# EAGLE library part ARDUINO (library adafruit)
Arduino Diecimila/Duemilanove Make a shield with ease, this package has all the named pins as well as the two mounting drill holes and an outline of the USB and DC power connector. The outline is on the DIMENSION layer, so if your board house uses it they will cut the outline to match. http://www.ladyada.net/library/pcb/eaglelibrary.html

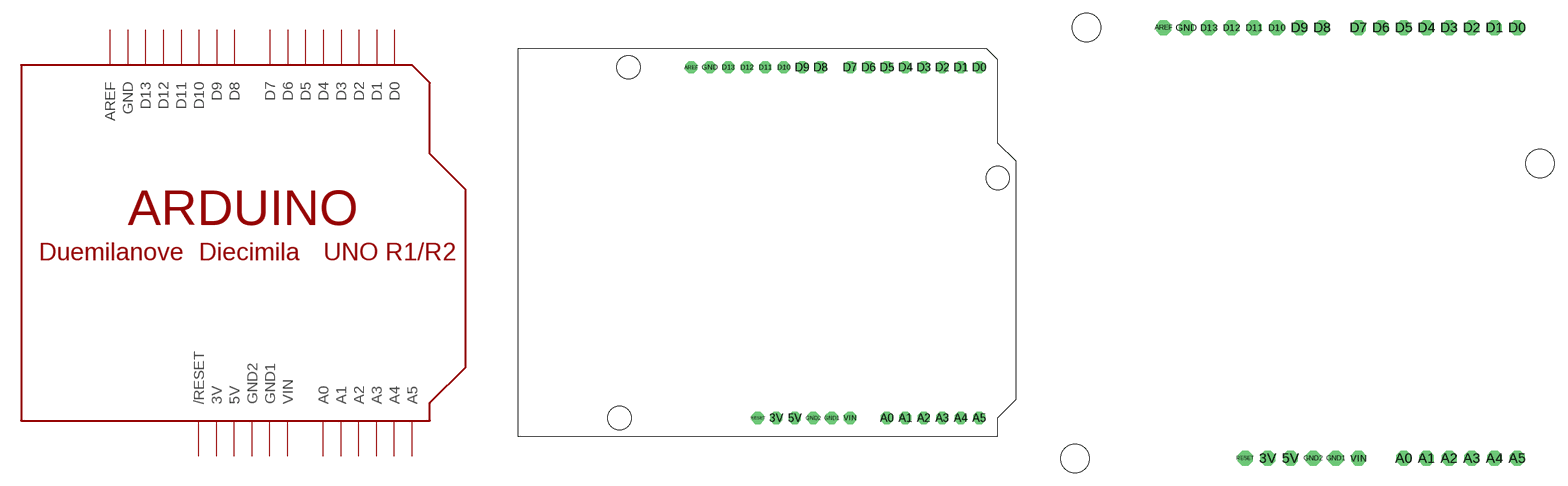
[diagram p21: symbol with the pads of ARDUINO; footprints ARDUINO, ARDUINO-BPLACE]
Designator prefix -

## ARDUINOUNO  [ARDUINO]
3V  3V  pwr
5V  5V  pwr
A0  A0
A1  A1
A2  A2
A3  A3
A4  A4
A5  A5
AREF  AREF
D0  D0
D1  D1
D2  D2
D3  D3
D4  D4
D5  D5
D6  D6
D7  D7
D8  D8
D9  D9
D10  D10
D11  D11
D12  D12
D13  D13
GND  GND  pwr
GND1  GND1  pwr
GND2  GND2  pwr
RESET  /RESET
VIN  VIN  pwr

## ARDUINO-BPLACE  [ARDUINO-BPLACE]
Pads as for ARDUINO

## ARDUINO-NOHOLE  [ARDUINO-NOHOLE]
Pads as for ARDUINO

## ARDUINO-NODIM  [ARDUINO-NODIM]
Pads as for ARDUINO

## Footprint ARDUINO (pad centres in mm)
Arduino Uno Make a shield with ease, this package has all the named pins as well as the two mounting drill holes and an outline of the USB and DC power connector. The outline is on the DIMENSION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
drill 1 pad 1.676 octagon: 3V 35.56,2.54; 5V 38.1,2.54; A0 50.8,2.54; A1 53.34,2.54; A2 55.88,2.54; A3 58.42,2.54; A4 60.96,2.54; A5 63.5,2.54; AREF 23.876,50.8; D0 63.5,50.8; D1 60.96,50.8; D2 58.42,50.8; D3 55.88,50.8; D4 53.34,50.8; D5 50.8,50.8; D6 48.26,50.8; D7 45.72,50.8; D8 41.656,50.8; D9 39.116,50.8; D10 36.576,50.8; D11 34.036,50.8; D12 31.496,50.8; D13 28.956,50.8; GND 26.416,50.8; GND1 43.18,2.54; GND2 40.64,2.54; RESET 33.02,2.54; VIN 45.72,2.54
hole 3.2 at 15.24,50.8
hole 3.2 at 66.04,35.56
hole 3.2 at 13.97,2.54

## Footprint ARDUINO-BPLACE (pad centres in mm)
drill 1 pad 1.676 octagon: 3V 35.56,2.54; 5V 38.1,2.54; A0 50.8,2.54; A1 53.34,2.54; A2 55.88,2.54; A3 58.42,2.54; A4 60.96,2.54; A5 63.5,2.54; AREF 23.876,50.8; D0 63.5,50.8; D1 60.96,50.8; D2 58.42,50.8; D3 55.88,50.8; D4 53.34,50.8; D5 50.8,50.8; D6 48.26,50.8; D7 45.72,50.8; D8 41.656,50.8; D9 39.116,50.8; D10 36.576,50.8; D11 34.036,50.8; D12 31.496,50.8; D13 28.956,50.8; GND 26.416,50.8; GND1 43.18,2.54; GND2 40.64,2.54; RESET 33.02,2.54; VIN 45.72,2.54
hole 3.2 at 15.24,50.8
hole 3.2 at 66.04,35.56
hole 3.2 at 13.97,2.54

## Footprint ARDUINO-NOHOLE (pad centres in mm)
drill 1 pad 1.676 octagon: 3V 35.56,2.54; 5V 38.1,2.54; A0 50.8,2.54; A1 53.34,2.54; A2 55.88,2.54; A3 58.42,2.54; A4 60.96,2.54; A5 63.5,2.54; AREF 23.876,50.8; D0 63.5,50.8; D1 60.96,50.8; D2 58.42,50.8; D3 55.88,50.8; D4 53.34,50.8; D5 50.8,50.8; D6 48.26,50.8; D7 45.72,50.8; D8 41.656,50.8; D9 39.116,50.8; D10 36.576,50.8; D11 34.036,50.8; D12 31.496,50.8; D13 28.956,50.8; GND 26.416,50.8; GND1 43.18,2.54; GND2 40.64,2.54; RESET 33.02,2.54; VIN 45.72,2.54

## Footprint ARDUINO-NODIM (pad centres in mm)
drill 1 pad 1.676 octagon: 3V 35.56,2.54; 5V 38.1,2.54; A0 50.8,2.54; A1 53.34,2.54; A2 55.88,2.54; A3 58.42,2.54; A4 60.96,2.54; A5 63.5,2.54; AREF 23.876,50.8; D0 63.5,50.8; D1 60.96,50.8; D2 58.42,50.8; D3 55.88,50.8; D4 53.34,50.8; D5 50.8,50.8; D6 48.26,50.8; D7 45.72,50.8; D8 41.656,50.8; D9 39.116,50.8; D10 36.576,50.8; D11 34.036,50.8; D12 31.496,50.8; D13 28.956,50.8; GND 26.416,50.8; GND1 43.18,2.54; GND2 40.64,2.54; RESET 33.02,2.54; VIN 45.72,2.54
hole 3.2 at 15.24,50.8
hole 3.2 at 66.04,35.56
hole 3.2 at 13.97,2.54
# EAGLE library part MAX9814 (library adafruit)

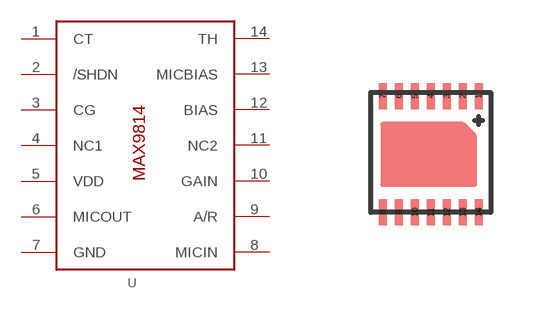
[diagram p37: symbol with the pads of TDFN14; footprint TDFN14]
Designator prefix -

## MAX9814TDFN  [TDFN14]
1  CT
2  /SHDN
3  CG
4  NC1  nc
5  VDD
6  MICOUT
7  GND
8  MICIN
9  A/R
10  GAIN
11  NC2  nc
12  BIAS
13  MICBIAS
14  TH

## Footprint TDFN14 (pad centres in mm)
smd 0.2 x 0.64: 1 1.2,1.4; 2 0.8,1.4; 3 0.4,1.4; 4 0,1.4; 5 -0.4,1.4; 6 -0.8,1.4; 7 -1.2,1.4; 8 -1.2,-1.5; 9 -0.8,-1.5; 10 -0.4,-1.5; 11 0,-1.5; 12 0.4,-1.5; 13 0.8,-1.5; 14 1.2,-1.5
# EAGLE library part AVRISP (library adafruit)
AVR ISP HEADER Standard 6 pin header for AVR programming

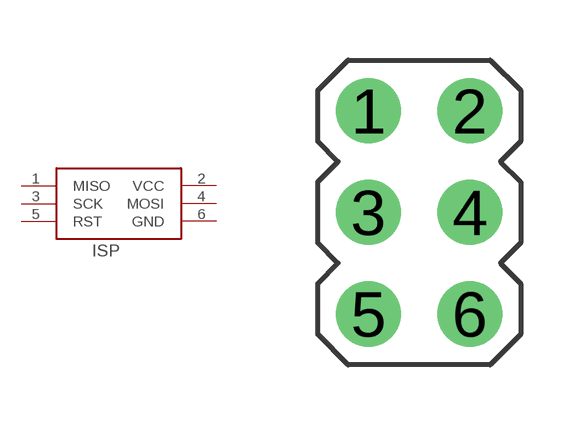
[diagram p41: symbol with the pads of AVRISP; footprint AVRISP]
Designator prefix ISP

## AVRISP-6  [AVRISP]
1  MISO  in
2  VCC  pwr
3  SCK  out
4  MOSI  out
5  RST  out
6  GND  pwr

## Footprint AVRISP (pad centres in mm)
drill 0.9 pad 1.626 round: 1 -1.27,2.54; 2 1.27,2.54; 3 -1.27,0; 4 1.27,0; 5 -1.27,-2.54; 6 1.27,-2.54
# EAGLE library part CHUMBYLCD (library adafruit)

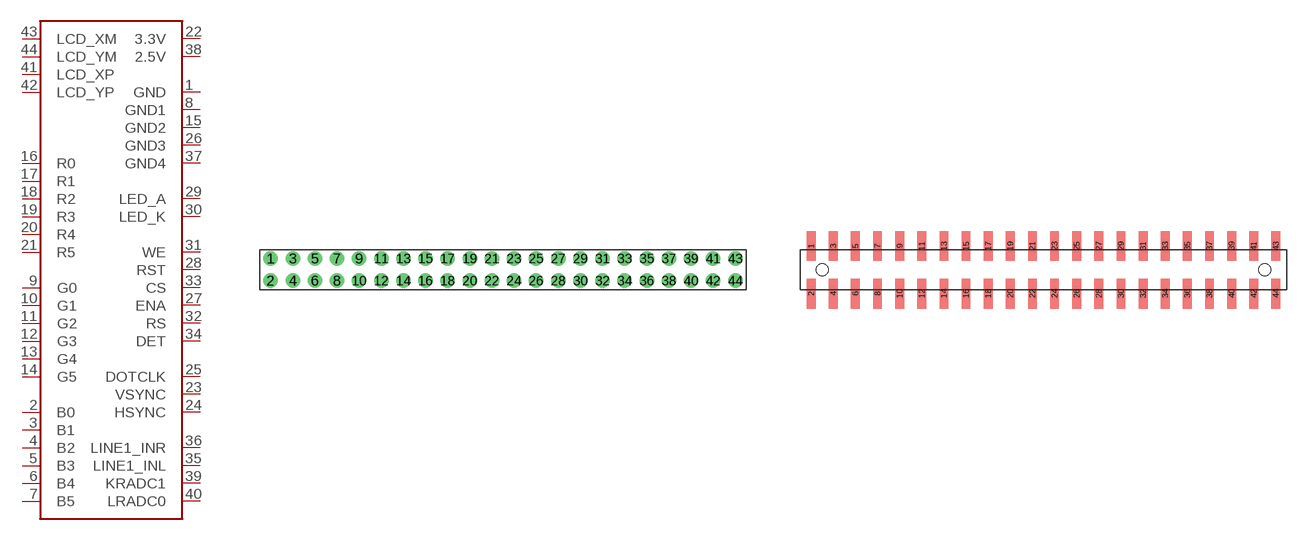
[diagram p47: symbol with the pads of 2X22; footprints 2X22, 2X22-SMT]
Designator prefix -

## CHUMBYLCD-THM  [2X22]
1  GND
2  B0
3  B1
4  B2
5  B3
6  B4
7  B5
8  GND1
9  G0
10  G1
11  G2
12  G3
13  G4
14  G5
15  GND2
16  R0
17  R1
18  R2
19  R3
20  R4
21  R5
22  3.3V
23  VSYNC
24  HSYNC
25  DOTCLK
26  GND3
27  ENA
28  RST
29  LED_A
30  LED_K
31  WE
32  RS
33  CS
34  DET
35  LINE1_INL
36  LINE1_INR
37  GND4
38  2.5V
39  KRADC1
40  LRADC0
41  LCD_XP
42  LCD_YP
43  LCD_XM
44  LCD_YM

## CHUMBYLCD-SMT  [2X22-SMT]
Pads as for 2X22

## Footprint 2X22 (pad centres in mm)
drill 0.8 round: 1 -21,1; 2 -21,-1; 3 -19,1; 4 -19,-1; 5 -17,1; 6 -17,-1; 7 -15,1; 8 -15,-1; 9 -13,1; 10 -13,-1; 11 -11,1; 12 -11,-1; 13 -9,1; 14 -9,-1; 15 -7,1; 16 -7,-1; 17 -5,1; 18 -5,-1; 19 -3,1; 20 -3,-1; 21 -1,1; 22 -1,-1; 23 1,1; 24 1,-1; 25 3,1; 26 3,-1; 27 5,1; 28 5,-1; 29 7,1; 30 7,-1; 31 9,1; 32 9,-1; 33 11,1; 34 11,-1; 35 13,1; 36 13,-1; 37 15,1; 38 15,-1; 39 17,1; 40 17,-1; 41 19,1; 42 19,-1; 43 21,1; 44 21,-1

## Footprint 2X22-SMT (pad centres in mm)
smd 0.8 x 2.7: 1 -21,2.15; 2 -21,-2.15; 3 -19,2.15; 4 -19,-2.15; 5 -17,2.15; 6 -17,-2.15; 7 -15,2.15; 8 -15,-2.15; 9 -13,2.15; 10 -13,-2.15; 11 -11,2.15; 12 -11,-2.15; 13 -9,2.15; 14 -9,-2.15; 15 -7,2.15; 16 -7,-2.15; 17 -5,2.15; 18 -5,-2.15; 19 -3,2.15; 20 -3,-2.15; 21 -1,2.15; 22 -1,-2.15; 23 1,2.15; 24 1,-2.15; 25 3,2.15; 26 3,-2.15; 27 5,2.15; 28 5,-2.15; 29 7,2.15; 30 7,-2.15; 31 9,2.15; 32 9,-2.15; 33 11,2.15; 34 11,-2.15; 35 13,2.15; 36 13,-2.15; 37 15,2.15; 38 15,-2.15; 39 17,2.15; 40 17,-2.15; 41 19,2.15; 42 19,-2.15; 43 21,2.15; 44 21,-2.15
hole 1.1 at -20,0
hole 1.1 at 20,0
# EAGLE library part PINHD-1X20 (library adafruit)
PIN HEADER

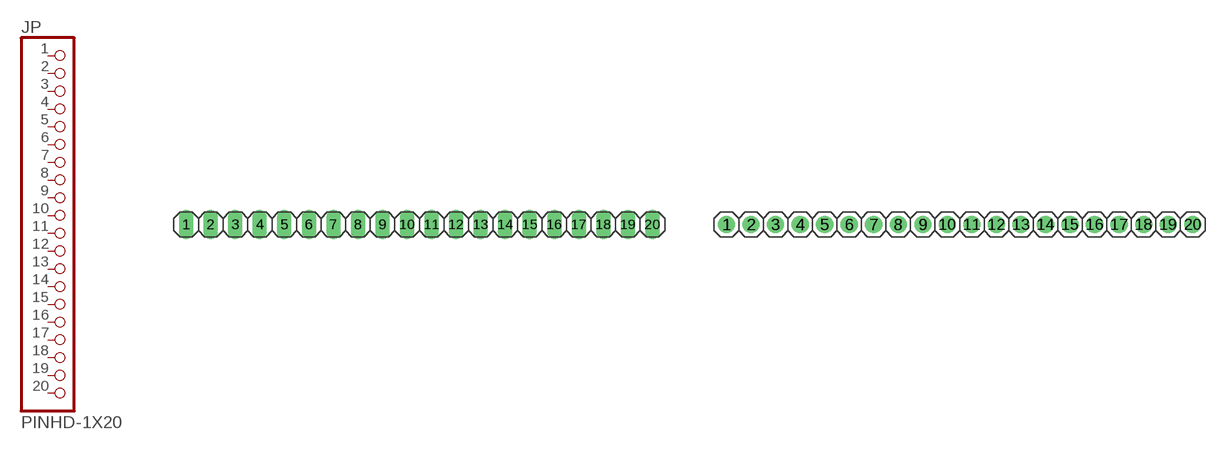
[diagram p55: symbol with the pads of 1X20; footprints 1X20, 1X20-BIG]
Designator prefix JP

## PINHD-1X20  [1X20]
1  1  pas
2  2  pas
3  3  pas
4  4  pas
5  5  pas
6  6  pas
7  7  pas
8  8  pas
9  9  pas
10  10  pas
11  11  pas
12  12  pas
13  13  pas
14  14  pas
15  15  pas
16  16  pas
17  17  pas
18  18  pas
19  19  pas
20  20  pas

## PINHD-1X20-BIG  [1X20-BIG]
Pads as for 1X20

## Footprint 1X20 (pad centres in mm)
PIN HEADER
drill 1.016 long: 1 -24.13,0; 2 -21.59,0; 3 -19.05,0; 4 -16.51,0; 5 -13.97,0; 6 -11.43,0; 7 -8.89,0; 8 -6.35,0; 9 -3.81,0; 10 -1.27,0; 11 1.27,0; 12 3.81,0; 13 6.35,0; 14 8.89,0; 15 11.43,0; 16 13.97,0; 17 16.51,0; 18 19.05,0; 19 21.59,0; 20 24.13,0

## Footprint 1X20-BIG (pad centres in mm)
drill 1.016 pad 1.778 round: 1 -24.13,0; 2 -21.59,0; 3 -19.05,0; 4 -16.51,0; 5 -13.97,0; 6 -11.43,0; 7 -8.89,0; 8 -6.35,0; 9 -3.81,0; 10 -1.27,0; 11 1.27,0; 12 3.81,0; 13 6.35,0; 14 8.89,0; 15 11.43,0; 16 13.97,0; 17 16.51,0; 18 19.05,0; 19 21.59,0; 20 24.13,0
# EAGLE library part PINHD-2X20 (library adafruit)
PIN HEADER

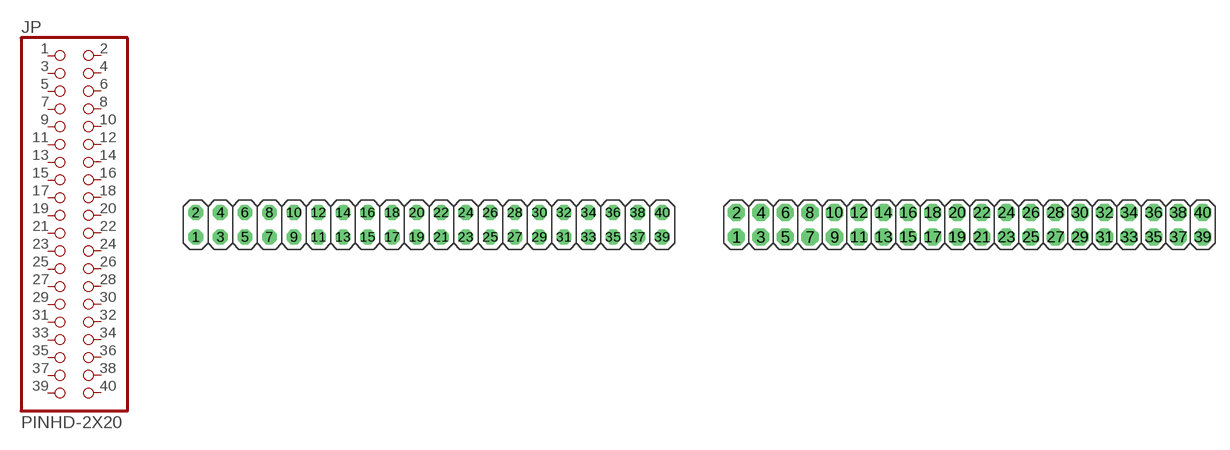
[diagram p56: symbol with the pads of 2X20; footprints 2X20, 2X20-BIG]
Designator prefix JP

## PINHD-2X20  [2X20]
1  1  pas
2  2  pas
3  3  pas
4  4  pas
5  5  pas
6  6  pas
7  7  pas
8  8  pas
9  9  pas
10  10  pas
11  11  pas
12  12  pas
13  13  pas
14  14  pas
15  15  pas
16  16  pas
17  17  pas
18  18  pas
19  19  pas
20  20  pas
21  21  pas
22  22  pas
23  23  pas
24  24  pas
25  25  pas
26  26  pas
27  27  pas
28  28  pas
29  29  pas
30  30  pas
31  31  pas
32  32  pas
33  33  pas
34  34  pas
35  35  pas
36  36  pas
37  37  pas
38  38  pas
39  39  pas
40  40  pas

## PINHD-2X20-BIG  [2X20-BIG]
Pads as for 2X20

## Footprint 2X20 (pad centres in mm)
PIN HEADER
drill 1.016 octagon: 1 -24.13,-1.27; 2 -24.13,1.27; 3 -21.59,-1.27; 4 -21.59,1.27; 5 -19.05,-1.27; 6 -19.05,1.27; 7 -16.51,-1.27; 8 -16.51,1.27; 9 -13.97,-1.27; 10 -13.97,1.27; 11 -11.43,-1.27; 12 -11.43,1.27; 13 -8.89,-1.27; 14 -8.89,1.27; 15 -6.35,-1.27; 16 -6.35,1.27; 17 -3.81,-1.27; 18 -3.81,1.27; 19 -1.27,-1.27; 20 -1.27,1.27; 21 1.27,-1.27; 22 1.27,1.27; 23 3.81,-1.27; 24 3.81,1.27; 25 6.35,-1.27; 26 6.35,1.27; 27 8.89,-1.27; 28 8.89,1.27; 29 11.43,-1.27; 30 11.43,1.27; 31 13.97,-1.27; 32 13.97,1.27; 33 16.51,-1.27; 34 16.51,1.27; 35 19.05,-1.27; 36 19.05,1.27; 37 21.59,-1.27; 38 21.59,1.27; 39 24.13,-1.27; 40 24.13,1.27

## Footprint 2X20-BIG (pad centres in mm)
drill 1.016 pad 1.778 octagon: 1 -24.13,-1.27; 2 -24.13,1.27; 3 -21.59,-1.27; 4 -21.59,1.27; 5 -19.05,-1.27; 6 -19.05,1.27; 7 -16.51,-1.27; 8 -16.51,1.27; 9 -13.97,-1.27; 10 -13.97,1.27; 11 -11.43,-1.27; 12 -11.43,1.27; 13 -8.89,-1.27; 14 -8.89,1.27; 15 -6.35,-1.27; 16 -6.35,1.27; 17 -3.81,-1.27; 18 -3.81,1.27; 19 -1.27,-1.27; 20 -1.27,1.27; 21 1.27,-1.27; 22 1.27,1.27; 23 3.81,-1.27; 24 3.81,1.27; 25 6.35,-1.27; 26 6.35,1.27; 27 8.89,-1.27; 28 8.89,1.27; 29 11.43,-1.27; 30 11.43,1.27; 31 13.97,-1.27; 32 13.97,1.27; 33 16.51,-1.27; 34 16.51,1.27; 35 19.05,-1.27; 36 19.05,1.27; 37 21.59,-1.27; 38 21.59,1.27; 39 24.13,-1.27; 40 24.13,1.27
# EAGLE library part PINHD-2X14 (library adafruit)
PIN HEADER

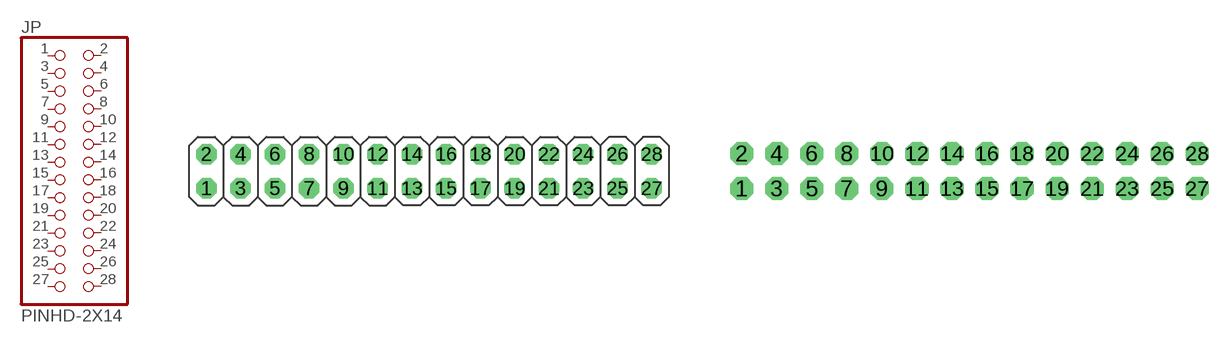
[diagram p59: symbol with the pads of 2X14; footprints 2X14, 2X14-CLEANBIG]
Designator prefix JP

## PINHD-2X14  [2X14]
1  1  pas
2  2  pas
3  3  pas
4  4  pas
5  5  pas
6  6  pas
7  7  pas
8  8  pas
9  9  pas
10  10  pas
11  11  pas
12  12  pas
13  13  pas
14  14  pas
15  15  pas
16  16  pas
17  17  pas
18  18  pas
19  19  pas
20  20  pas
21  21  pas
22  22  pas
23  23  pas
24  24  pas
25  25  pas
26  26  pas
27  27  pas
28  28  pas

## PINHD-2X14-CB  [2X14-CLEANBIG]
Pads as for 2X14

## PINHD-2X14-SMT  [2X14-SMT]
Pads as for 2X14

## Footprint 2X14 (pad centres in mm)
PIN HEADER
drill 1.016 octagon: 1 -16.51,-1.27; 2 -16.51,1.27; 3 -13.97,-1.27; 4 -13.97,1.27; 5 -11.43,-1.27; 6 -11.43,1.27; 7 -8.89,-1.27; 8 -8.89,1.27; 9 -6.35,-1.27; 10 -6.35,1.27; 11 -3.81,-1.27; 12 -3.81,1.27; 13 -1.27,-1.27; 14 -1.27,1.27; 15 1.27,-1.27; 16 1.27,1.27; 17 3.81,-1.27; 18 3.81,1.27; 19 6.35,-1.27; 20 6.35,1.27; 21 8.89,-1.27; 22 8.89,1.27; 23 11.43,-1.27; 24 11.43,1.27; 25 13.97,-1.27; 26 13.97,1.27; 27 16.51,-1.27; 28 16.51,1.27

## Footprint 2X14-CLEANBIG (pad centres in mm)
drill 1.016 pad 1.676 octagon: 1 -16.51,-1.27; 2 -16.51,1.27; 3 -13.97,-1.27; 4 -13.97,1.27; 5 -11.43,-1.27; 6 -11.43,1.27; 7 -8.89,-1.27; 8 -8.89,1.27; 9 -6.35,-1.27; 10 -6.35,1.27; 11 -3.81,-1.27; 12 -3.81,1.27; 13 -1.27,-1.27; 14 -1.27,1.27; 15 1.27,-1.27; 16 1.27,1.27; 17 3.81,-1.27; 18 3.81,1.27; 19 6.35,-1.27; 20 6.35,1.27; 21 8.89,-1.27; 22 8.89,1.27; 23 11.43,-1.27; 24 11.43,1.27; 25 13.97,-1.27; 26 13.97,1.27; 27 16.51,-1.27; 28 16.51,1.27

## Footprint 2X14-SMT (pad centres in mm)
smd 1.27 x 2.032: 1 -16.51,-2.921; 2 -16.51,2.921; 3 -13.97,-2.921; 4 -13.97,2.921; 5 -11.43,-2.921; 6 -11.43,2.921; 7 -8.89,-2.921; 8 -8.89,2.921; 9 -6.35,-2.921; 10 -6.35,2.921; 11 -3.81,-2.921; 12 -3.81,2.921; 13 -1.27,-2.921; 14 -1.27,2.921; 15 1.27,-2.921; 16 1.27,2.921; 17 3.81,-2.921; 18 3.81,2.921; 19 6.35,-2.921; 20 6.35,2.921; 21 8.89,-2.921; 22 8.89,2.921; 23 11.43,-2.921; 24 11.43,2.921; 25 13.97,-2.921; 26 13.97,2.921; 27 16.51,-2.921; 28 16.51,2.921
hole 1 at -15.24,0
hole 1 at 15.24,0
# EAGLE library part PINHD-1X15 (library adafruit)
PIN HEADER

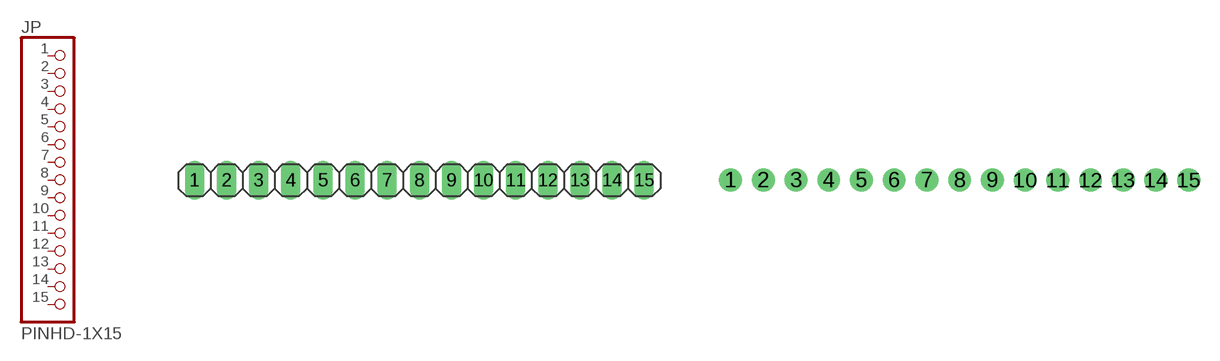
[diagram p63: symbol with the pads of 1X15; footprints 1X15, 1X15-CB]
Designator prefix JP

## PINHD-1X15  [1X15]
1  1  pas
2  2  pas
3  3  pas
4  4  pas
5  5  pas
6  6  pas
7  7  pas
8  8  pas
9  9  pas
10  10  pas
11  11  pas
12  12  pas
13  13  pas
14  14  pas
15  15  pas

## PINHD-1X15-CB  [1X15-CB]
Pads as for 1X15

## Footprint 1X15 (pad centres in mm)
PIN HEADER
drill 1.016 long: 1 -17.78,0; 2 -15.24,0; 3 -12.7,0; 4 -10.16,0; 5 -7.62,0; 6 -5.08,0; 7 -2.54,0; 8 0,0; 9 2.54,0; 10 5.08,0; 11 7.62,0; 12 10.16,0; 13 12.7,0; 14 15.24,0; 15 17.78,0

## Footprint 1X15-CB (pad centres in mm)
drill 1.016 pad 1.778 round: 1 -17.78,0; 2 -15.24,0; 3 -12.7,0; 4 -10.16,0; 5 -7.62,0; 6 -5.08,0; 7 -2.54,0; 8 0,0; 9 2.54,0; 10 5.08,0; 11 7.62,0; 12 10.16,0; 13 12.7,0; 14 15.24,0; 15 17.78,0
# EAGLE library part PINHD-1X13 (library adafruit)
PIN HEADER

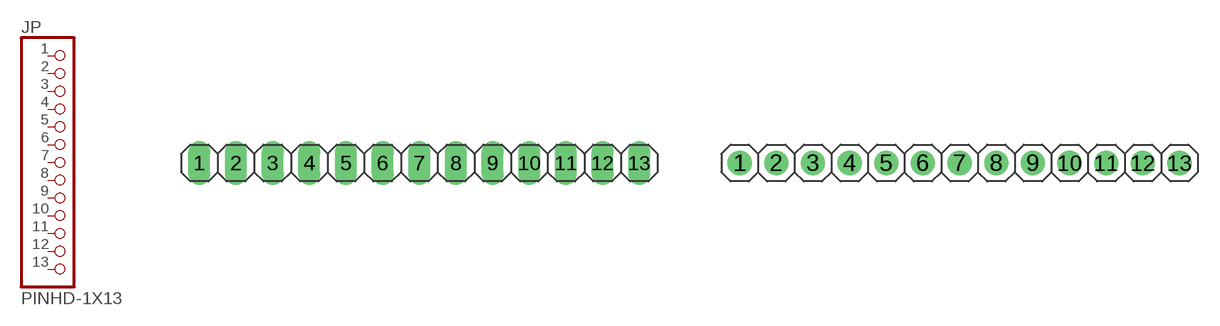
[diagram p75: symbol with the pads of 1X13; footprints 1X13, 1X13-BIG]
Designator prefix JP

## PINHD-1X13  [1X13]
1  1  pas
2  2  pas
3  3  pas
4  4  pas
5  5  pas
6  6  pas
7  7  pas
8  8  pas
9  9  pas
10  10  pas
11  11  pas
12  12  pas
13  13  pas

## PINHD-1X13_BIG  [1X13-BIG]
Pads as for 1X13

## Footprint 1X13 (pad centres in mm)
PIN HEADER
drill 1.016 long: 1 -15.24,0; 2 -12.7,0; 3 -10.16,0; 4 -7.62,0; 5 -5.08,0; 6 -2.54,0; 7 0,0; 8 2.54,0; 9 5.08,0; 10 7.62,0; 11 10.16,0; 12 12.7,0; 13 15.24,0

## Footprint 1X13-BIG (pad centres in mm)
drill 1.016 pad 1.676 round: 1 -15.24,0; 2 -12.7,0; 3 -10.16,0; 4 -7.62,0; 5 -5.08,0; 6 -2.54,0; 7 0,0; 8 2.54,0; 9 5.08,0; 10 7.62,0; 11 10.16,0; 12 12.7,0; 13 15.24,0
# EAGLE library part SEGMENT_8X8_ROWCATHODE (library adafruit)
8x8 LED Segment Displays: Row = Cathode 0.7" Red 8X8 Matrix, 1.9mm Round LEDs - BL-M07C881UR 1.2" Red 8x8 Matrix, 3.0mm Round LEDs - BL-M12A881UR 1.2" Red 8x8 Matrix, 3.0mm Square LEDs - BL-M12A883

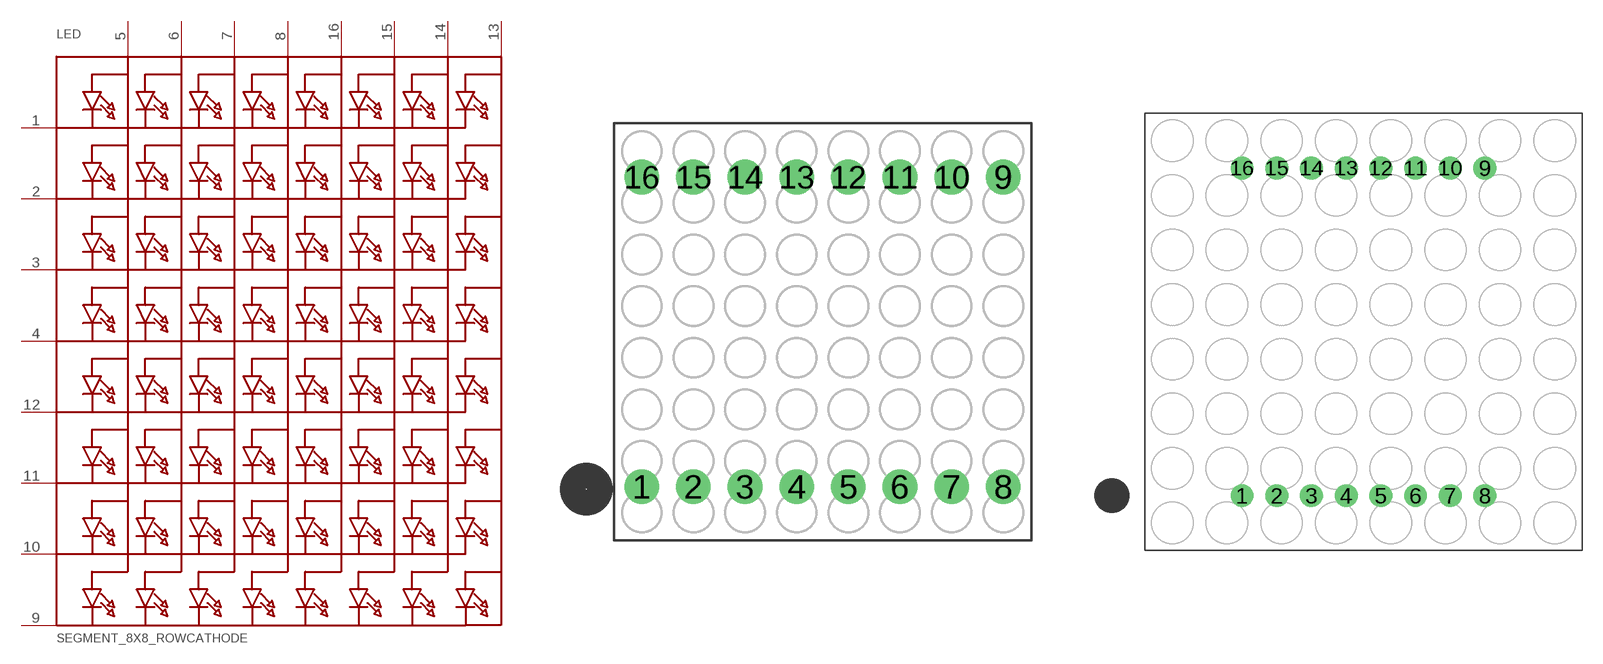
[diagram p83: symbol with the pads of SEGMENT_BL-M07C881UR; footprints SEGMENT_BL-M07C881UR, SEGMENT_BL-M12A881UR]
Designator prefix LED

## SEGMENT_8X8_ROWCATHODE  [SEGMENT_BL-M07C881UR]
1  K1
2  K2
3  K3
4  K4
5  A1
6  A2
7  A3
8  A4
9  K8
10  K7
11  K6
12  K5
13  A8
14  A7
15  A6
16  A5

## SEGMENT_8X8_ROWCATHODEM12A881UR  [SEGMENT_BL-M12A881UR]
1  K5
2  K7
3  A2
4  A3
5  K8
6  A5
7  K6
8  K3
9  K1
10  A4
11  A6
12  K4
13  A1
14  K2
15  A7
16  A8

## SEGMENT_8X8_ROWCATHODEBL-M12A883  [SEGMENT_BL-M12A883]
Pads as for SEGMENT_BL-M12A881UR

## SEGMENT_8X8_ROWCATHODEBL-M15  [SEGMENT_BL-M15A881]
Pads as for SEGMENT_BL-M12A881UR

## Footprint SEGMENT_BL-M07C881UR (pad centres in mm)
drill 0.8 pad 1.676 round: 1 -8.75,-7.5; 2 -6.25,-7.5; 3 -3.75,-7.5; 4 -1.25,-7.5; 5 1.25,-7.5; 6 3.75,-7.5; 7 6.25,-7.5; 8 8.75,-7.5; 9 8.75,7.5; 10 6.25,7.5; 11 3.75,7.5; 12 1.25,7.5; 13 -1.25,7.5; 14 -3.75,7.5; 15 -6.25,7.5; 16 -8.75,7.5

## Footprint SEGMENT_BL-M12A881UR (pad centres in mm)
Source: http://www.betlux.com/product/LED_dot_matrix/BL-M12A881.PDF
drill 0.8 pad 1.676 round: 1 -8.89,-12; 2 -6.35,-12; 3 -3.81,-12; 4 -1.27,-12; 5 1.27,-12; 6 3.81,-12; 7 6.35,-12; 8 8.89,-12; 9 8.89,12; 10 6.35,12; 11 3.81,12; 12 1.27,12; 13 -1.27,12; 14 -3.81,12; 15 -6.35,12; 16 -8.89,12

## Footprint SEGMENT_BL-M12A883 (pad centres in mm)
Source: http://www.betlux.com/product/LED_dot_matrix/BL-M12A883.PDF
drill 0.8 pad 1.676 round: 1 -8.89,-12; 2 -6.35,-12; 3 -3.81,-12; 4 -1.27,-12; 5 1.27,-12; 6 3.81,-12; 7 6.35,-12; 8 8.89,-12; 9 8.89,12; 10 6.35,12; 11 3.81,12; 12 1.27,12; 13 -1.27,12; 14 -3.81,12; 15 -6.35,12; 16 -8.89,12

## Footprint SEGMENT_BL-M15A881 (pad centres in mm)
drill 0.8 pad 1.676 round: 1 -8.89,-14.2; 2 -6.35,-14.2; 3 -3.81,-14.2; 4 -1.27,-14.2; 5 1.27,-14.2; 6 3.81,-14.2; 7 6.35,-14.2; 8 8.89,-14.2; 9 8.89,14.2; 10 6.35,14.2; 11 3.81,14.2; 12 1.27,14.2; 13 -1.27,14.2; 14 -3.81,14.2; 15 -6.35,14.2; 16 -8.89,14.2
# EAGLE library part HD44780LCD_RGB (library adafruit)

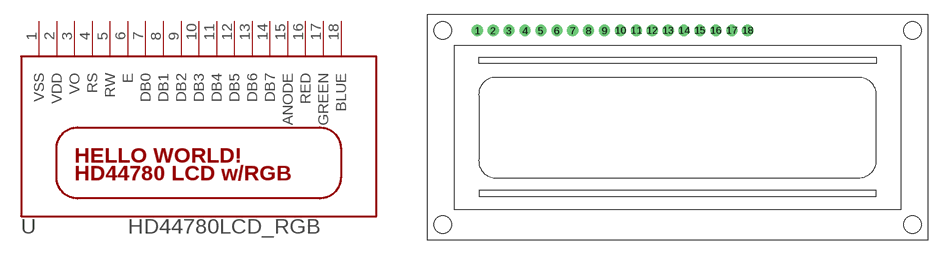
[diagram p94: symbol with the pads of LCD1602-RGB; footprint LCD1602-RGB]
Designator prefix -

## HD44780LCD_RGBLONGPINS  [LCD1602-RGB]
1  VSS  sup
2  VDD  sup
3  VO  in
4  RS  in
5  RW  in
6  E  in
7  DB0
8  DB1
9  DB2
10  DB3
11  DB4
12  DB5
13  DB6
14  DB7
15  ANODE  in
16  RED  in
17  GREEN  in
18  BLUE  in

## Footprint LCD1602-RGB (pad centres in mm)
drill 1 pad 1.778 round: 1 -32,15.5; 2 -29.46,15.5; 3 -26.92,15.5; 4 -24.38,15.5; 5 -21.84,15.5; 6 -19.3,15.5; 7 -16.76,15.5; 8 -14.22,15.5; 9 -11.68,15.5; 10 -9.14,15.5; 11 -6.6,15.5; 12 -4.06,15.5; 13 -1.52,15.5; 14 1.02,15.5; 15 3.56,15.5; 16 6.1,15.5; 17 8.64,15.5; 18 11.18,15.5
hole 2.8 at -37.5,-15.5
hole 2.8 at -37.5,15.5
hole 2.8 at 37.5,15.5
hole 2.8 at 37.5,-15.5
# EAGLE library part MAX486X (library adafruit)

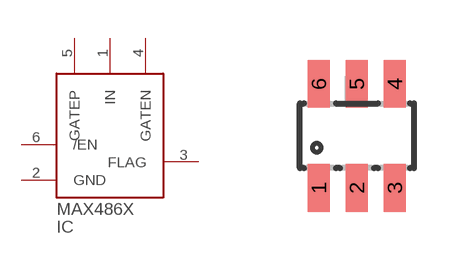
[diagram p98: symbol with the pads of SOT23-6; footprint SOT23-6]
Designator prefix IC

## MAX486X/SOT  [SOT23-6]
1  IN  in
2  GND  pwr
3  FLAG  out
4  GATEN  out
5  GATEP  out
6  /EN  in

## Footprint SOT23-6 (pad centres in mm)
smd 0.55 x 1.2: 1 -0.95,-1.3; 2 0,-1.3; 3 0.95,-1.3; 4 0.95,1.3; 5 0,1.3; 6 -0.95,1.3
